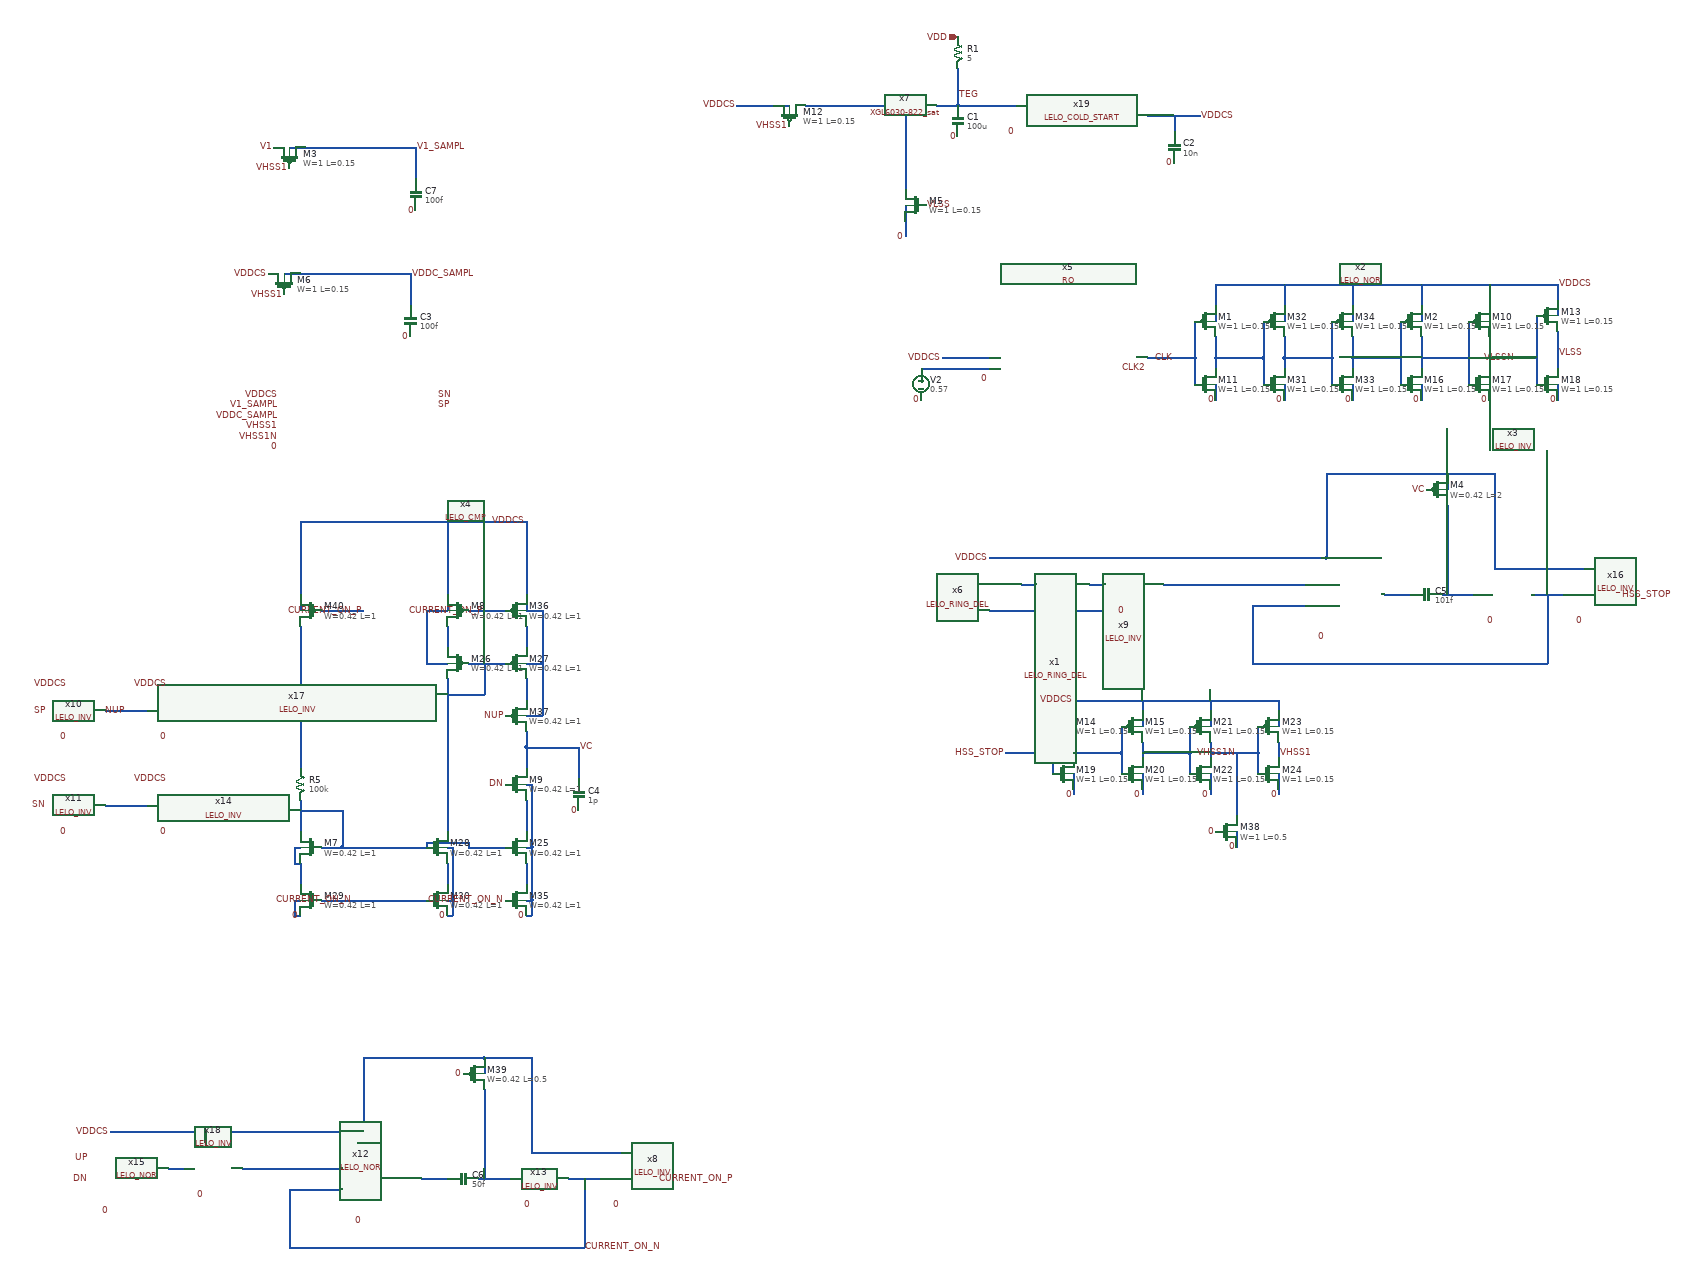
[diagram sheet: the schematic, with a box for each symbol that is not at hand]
v {xschem version=3.4.8RC file_version=1.2}
G {}
K {}
V {}
S {}
E {}
N -200 -370 -200 -300 {lab=TEG}
N -490 -300 -430 -300 {lab=V1}
N -430 -300 -300 -300 {lab=V1}
N -300 -300 -300 -140 {lab=V1}
N -300 -110 -300 -50 {lab=0}
N -240 -300 -220 -300 {lab=TEG}
N 290 230 290 260 {lab=0}
N 160 180 250 180 {lab=CLK}
N 680 140 680 200 {lab=#net1}
N 680 230 680 260 {lab=0}
N 640 110 640 230 {lab=#net2}
N 290 180 380 180 {lab=#net3}
N -220 -300 -200 -300 {lab=TEG}
N 60 610 80 610 {lab=#net4}
N 50 610 60 610 {lab=#net4}
N 810 140 810 200 {lab=VLSSN}
N 810 230 810 260 {lab=0}
N 770 110 770 230 {lab=#net1}
N 680 180 770 180 {lab=#net1}
N 940 130 940 200 {lab=VLSS}
N 940 230 940 260 {lab=0}
N 900 100 900 230 {lab=VLSSN}
N 810 180 900 180 {lab=VLSSN}
N -550 -300 -520 -300 {lab=VDDCS}
N -1330 -220 -1230 -220 {lab=V1_SAMPL}
N -1230 -220 -1230 -160 {lab=V1_SAMPL}
N -1470 -220 -1440 -220 {lab=V1_SAMPL}
N -1440 -220 -1330 -220 {lab=V1_SAMPL}
N -1340 20 -1240 20 {lab=VDDC_SAMPL}
N -1240 20 -1240 80 {lab=VDDC_SAMPL}
N -1480 20 -1450 20 {lab=VDDC_SAMPL}
N -1450 20 -1340 20 {lab=VDDC_SAMPL}
N -1020 920 -920 920 {lab=VC}
N -920 920 -920 980 {lab=VC}
N -1020 920 -1020 960 {lab=VC}
N -1020 1020 -1020 1080 {lab=#net5}
N -270 200 -140 200 {lab=#net6}
N -1020 790 -1020 830 {lab=#net7}
N -1020 890 -1020 920 {lab=VC}
N 290 40 870 40 {lab=#net8}
N 680 40 680 80 {lab=#net8}
N 810 40 810 80 {lab=#net8}
N 940 40 940 70 {lab=#net8}
N 290 40 290 80 {lab=#net8}
N 290 140 290 180 {lab=#net3}
N 290 180 290 200 {lab=#net3}
N 250 110 250 180 {lab=CLK}
N 250 180 250 230 {lab=CLK}
N 20 830 20 850 {lab=VDDCS}
N 150 830 150 850 {lab=VDDCS}
N 20 970 20 1000 {lab=0}
N 150 970 150 1000 {lab=0}
N -110 930 -20 930 {lab=HSS_STOP}
N -20 880 -20 930 {lab=HSS_STOP}
N -20 930 -20 970 {lab=HSS_STOP}
N 20 910 20 940 {lab=#net9}
N 20 1000 20 1010 {lab=0}
N 20 930 110 930 {lab=#net9}
N 110 880 110 930 {lab=#net9}
N 110 930 110 970 {lab=#net9}
N 150 910 150 940 {lab=#net10}
N 150 1000 150 1010 {lab=0}
N 280 830 280 850 {lab=VDDCS}
N 280 970 280 1000 {lab=0}
N 150 930 240 930 {lab=#net10}
N 240 880 240 930 {lab=#net10}
N 240 930 240 970 {lab=#net10}
N 280 910 280 940 {lab=VHSS1N}
N 280 1000 280 1010 {lab=0}
N 410 830 410 850 {lab=VDDCS}
N 410 970 410 1000 {lab=0}
N 370 880 370 930 {lab=VHSS1N}
N 370 930 370 970 {lab=VHSS1N}
N 410 910 410 940 {lab=VHSS1}
N 410 1000 410 1010 {lab=0}
N 290 80 290 110 {lab=#net8}
N 680 80 680 110 {lab=#net8}
N 810 80 810 110 {lab=#net8}
N 940 70 940 100 {lab=#net8}
N 20 850 20 880 {lab=VDDCS}
N 150 850 150 880 {lab=VDDCS}
N 280 850 280 880 {lab=VDDCS}
N 410 850 410 880 {lab=VDDCS}
N -230 180 -140 180 {lab=#net11}
N 190 610 270 610 {lab=#net12}
N 420 230 420 260 {lab=0}
N 420 180 510 180 {lab=#net13}
N 420 40 420 80 {lab=#net8}
N 420 140 420 180 {lab=#net13}
N 420 180 420 200 {lab=#net13}
N 380 110 380 180 {lab=#net3}
N 380 180 380 230 {lab=#net3}
N 420 80 420 110 {lab=#net8}
N 550 230 550 260 {lab=0}
N 550 180 640 180 {lab=#net2}
N 550 40 550 80 {lab=#net8}
N 550 140 550 180 {lab=#net2}
N 550 180 550 200 {lab=#net2}
N 510 110 510 180 {lab=#net13}
N 510 180 510 230 {lab=#net13}
N 550 80 550 110 {lab=#net8}
N 270 610 460 610 {lab=#net12}
N 890 630 950 630 {lab=#net14}
N 820 580 990 580 {lab=VDDCS}
N 720 630 780 630 {lab=#net15}
N 610 630 660 630 {lab=#net16}
N 490 560 500 560 {lab=VDDCS}
N 360 760 920 760 {lab=#net14}
N 360 650 460 650 {lab=#net14}
N 730 460 730 630 {lab=#net15}
N 730 400 730 430 {lab=VDDCS}
N 360 650 360 760 {lab=#net14}
N 920 630 920 760 {lab=#net14}
N 820 400 820 580 {lab=VDDCS}
N 730 400 820 400 {lab=VDDCS}
N 500 400 730 400 {lab=VDDCS}
N 500 400 500 560 {lab=VDDCS}
N 120 560 500 560 {lab=VDDCS}
N -140 560 120 560 {lab=VDDCS}
N -140 660 120 660 {lab=0}
N -80 610 -50 610 {lab=#net17}
N -1450 1020 -1450 1080 {lab=#net18}
N -1370 1040 -1370 1110 {lab=#net18}
N -1450 1040 -1370 1040 {lab=#net18}
N -1130 760 -1060 760 {lab=#net19}
N -1170 820 -1100 820 {lab=#net19}
N -1100 760 -1100 820 {lab=#net19}
N -1450 1140 -1450 1180 {lab=#net20}
N -1020 1140 -1020 1180 {lab=#net21}
N -1410 1110 -1370 1110 {lab=#net18}
N -1370 1110 -1210 1110 {lab=#net18}
N -1170 790 -1170 1080 {lab=#net19}
N -1170 1140 -1170 1180 {lab=#net22}
N -1450 690 -1450 960 {lab=#net23}
N -1130 660 -1060 660 {lab=CURRENT_ON_P}
N -1020 690 -1020 730 {lab=#net24}
N -1170 690 -1170 730 {lab=#net25}
N -1130 1110 -1060 1110 {lab=#net18}
N -1170 1110 -1160 1110 {lab=0}
N -1160 1110 -1160 1210 {lab=0}
N -1170 1210 -1160 1210 {lab=0}
N -1170 1210 -1160 1210 {lab=0}
N -1160 1210 -1160 1240 {lab=0}
N -1170 1240 -1160 1240 {lab=0}
N -1020 1110 -1010 1110 {lab=0}
N -1010 1110 -1010 1210 {lab=0}
N -1020 1210 -1010 1210 {lab=0}
N -1020 1210 -1010 1210 {lab=0}
N -1010 1210 -1010 1240 {lab=0}
N -1020 1240 -1010 1240 {lab=0}
N -1460 1210 -1450 1210 {lab=0}
N -1460 1210 -1460 1240 {lab=0}
N -1460 1240 -1450 1240 {lab=0}
N -1460 1110 -1450 1110 {lab=#net20}
N -1460 1110 -1460 1140 {lab=#net20}
N -1460 1140 -1450 1140 {lab=#net20}
N -1560 1720 -1370 1720 {lab=#net26}
N -940 1740 -880 1740 {lab=CURRENT_ON_N}
N -1010 1690 -840 1690 {lab=VDDCS}
N -1110 1740 -1050 1740 {lab=#net27}
N -1220 1740 -1170 1740 {lab=#net28}
N -1340 1670 -1330 1670 {lab=VDDCS}
N -1470 1870 -910 1870 {lab=CURRENT_ON_N}
N -1470 1760 -1370 1760 {lab=CURRENT_ON_N}
N -1100 1570 -1100 1740 {lab=#net27}
N -1100 1510 -1100 1540 {lab=VDDCS}
N -1470 1760 -1470 1870 {lab=CURRENT_ON_N}
N -910 1740 -910 1870 {lab=CURRENT_ON_N}
N -1010 1510 -1010 1690 {lab=VDDCS}
N -1100 1510 -1010 1510 {lab=VDDCS}
N -1330 1510 -1100 1510 {lab=VDDCS}
N -1330 1510 -1330 1670 {lab=VDDCS}
N -1410 1210 -1350 1210 {lab=CURRENT_ON_N}
N -1350 1210 -1210 1210 {lab=CURRENT_ON_N}
N -1410 660 -1330 660 {lab=CURRENT_ON_P}
N -1020 490 -1020 630 {lab=VDDCS}
N -1450 490 -1020 490 {lab=VDDCS}
N -1450 490 -1450 630 {lab=VDDCS}
N -1170 490 -1170 630 {lab=VDDCS}
N -1210 1100 -1210 1110 {lab=#net18}
N -1210 1100 -1130 1100 {lab=#net18}
N -1130 1100 -1130 1110 {lab=#net18}
N -1210 760 -1170 760 {lab=VDDCS}
N -1210 660 -1210 760 {lab=VDDCS}
N -1210 660 -1170 660 {lab=VDDCS}
N -1170 630 -1170 660 {lab=VDDCS}
N -1020 760 -990 760 {lab=VDDCS}
N -990 660 -990 760 {lab=VDDCS}
N -1020 660 -990 660 {lab=VDDCS}
N -1020 630 -1020 660 {lab=VDDCS}
N -1450 630 -1450 660 {lab=VDDCS}
N -1020 860 -990 860 {lab=VDDCS}
N -990 760 -990 860 {lab=VDDCS}
N -1820 1030 -1740 1030 {lab=#net29}
N -1820 850 -1740 850 {lab=NUP}
N -1700 1720 -1670 1720 {lab=#net30}
N -1810 1650 -1330 1650 {lab=VDDCS}
N -1630 1650 -1630 1670 {lab=VDDCS}
N -1020 990 -1010 990 {lab=0}
N -1010 990 -1010 1110 {lab=0}
N 20 830 410 830 {lab=VDDCS}
N 280 930 370 930 {lab=VHSS1N}
N 211 -280 211 -250 {lab=VDDCS}
N 161 -280 211 -280 {lab=VDDCS}
N -130 -300 -89 -300 {lab=TEG}
N -200 -300 -130 -300 {lab=TEG}
N 210 -280 260 -280 {lab=VDDCS}
N -620 -300 -550 -300 {lab=VDDCS}
N 870 40 940 40 {lab=#net8}
N 330 1080 330 1110 {lab=0}
N 330 930 330 1050 {lab=VHSS1N}
C {devices/ipin.sym} -200 -430 0 0 {name=p2 lab=VDD}
C {devices/lab_pin.sym} -300 -300 1 0 {name=p3 sig_type=std_logic lab=V1}
C {devices/res.sym} -200 -400 0 0 {name=R1
value=5
footprint=1206
device=resistor
m=1}
C {devices/lab_pin.sym} -300 -50 1 1 {name=p29 sig_type=std_logic lab=0}
C {devices/capa.sym} -1230 -130 0 0 {name=C7
m=1
value=100f
footprint=1206
device="ceramic capacitor"}
C {devices/lab_pin.sym} -1230 -100 1 1 {name=p34 sig_type=std_logic lab=0}
C {devices/lab_pin.sym} 20 1010 3 0 {name=p77 sig_type=std_logic lab=0}
C {LELO_SVOD_SKY130A/RO.sym} 10 200 0 0 {name=x5}
C {devices/lab_pin.sym} -140 220 3 0 {name=p13 sig_type=std_logic lab=0}
C {devices/lab_pin.sym} 210 180 1 1 {name=p14 sig_type=std_logic lab=CLK}
C {devices/lab_pin.sym} 290 260 3 0 {name=p15 sig_type=std_logic lab=0}
C {devices/lab_pin.sym} 680 260 3 0 {name=p17 sig_type=std_logic lab=0}
C {devices/lab_pin.sym} 940 170 0 1 {name=p30 sig_type=std_logic lab=VLSS}
C {devices/lab_pin.sym} -260 -110 0 1 {name=p66 sig_type=std_logic lab=VLSS}
C {devices/lab_pin.sym} -180 610 0 0 {name=p23 sig_type=std_logic lab=VLSS}
C {sky130_fd_pr/pfet_01v8.sym} -520 -280 3 0 {name=M12
W=1
L=0.15
nf=1
mult=800
ad="expr('int((@nf + 1)/2) * @W / @nf * 0.29')"
pd="expr('2*int((@nf + 1)/2) * (@W / @nf + 0.29)')"
as="expr('int((@nf + 2)/2) * @W / @nf * 0.29')"
ps="expr('2*int((@nf + 2)/2) * (@W / @nf + 0.29)')"
nrd="expr('0.29 / @W ')" nrs="expr('0.29 / @W ')"
sa=0 sb=0 sd=0
model=pfet_01v8
spiceprefix=X
}
C {devices/lab_pin.sym} 150 1010 3 0 {name=p4 sig_type=std_logic lab=0}
C {LELO_SVOD_SKY130A/LELO_INV.sym} 1010 630 0 0 {name=x16}
C {devices/capa.sym} -200 -270 0 0 {name=C1
m=1
value=100u
footprint=1206
device="ceramic capacitor"}
C {devices/lab_pin.sym} -200 -240 1 1 {name=p7 sig_type=std_logic lab=0}
C {LELO_SVOD_SKY130A/LELO_INV.sym} 140 610 0 0 {name=x9}
C {sky130_fd_pr/nfet_01v8_lvt.sym} -280 -110 0 1 {name=M5
W=1
L=0.15
nf=1
mult=6500
ad="expr('int((@nf + 1)/2) * @W / @nf * 0.29')"
pd="expr('2*int((@nf + 1)/2) * (@W / @nf + 0.29)')"
as="expr('int((@nf + 2)/2) * @W / @nf * 0.29')"
ps="expr('2*int((@nf + 2)/2) * (@W / @nf + 0.29)')"
nrd="expr('0.29 / @W ')" nrs="expr('0.29 / @W ')"
sa=0 sb=0 sd=0
model=nfet_01v8_lvt
spiceprefix=X
}
C {devices/lab_pin.sym} 810 260 3 0 {name=p51 sig_type=std_logic lab=0}
C {devices/lab_pin.sym} 940 260 3 0 {name=p90 sig_type=std_logic lab=0}
C {devices/lab_pin.sym} -200 -320 2 0 {name=p93 sig_type=std_logic lab=TEG}
C {devices/lab_pin.sym} 160 200 1 1 {name=p94 sig_type=std_logic lab=CLK2}
C {devices/lab_pin.sym} -620 -300 2 1 {name=p24 sig_type=std_logic lab=VDDCS}
C {LELO_SVOD_SKY130A/LELO_CMP.sym} -1340 300 0 0 {name=x4}
C {devices/lab_pin.sym} -1470 -180 1 1 {name=p10 sig_type=std_logic lab=VHSS1}
C {sky130_fd_pr/pfet_01v8.sym} -1470 -200 1 1 {name=M3
W=1
L=0.15
nf=1
mult=1
ad="expr('int((@nf + 1)/2) * @W / @nf * 0.29')"
pd="expr('2*int((@nf + 1)/2) * (@W / @nf + 0.29)')"
as="expr('int((@nf + 2)/2) * @W / @nf * 0.29')"
ps="expr('2*int((@nf + 2)/2) * (@W / @nf + 0.29)')"
nrd="expr('0.29 / @W ')" nrs="expr('0.29 / @W ')"
sa=0 sb=0 sd=0
model=pfet_01v8
spiceprefix=X
}
C {devices/lab_pin.sym} -1500 -220 0 0 {name=p12 sig_type=std_logic lab=V1}
C {devices/capa.sym} -1240 110 0 0 {name=C3
m=1
value=100f
footprint=1206
device="ceramic capacitor"}
C {devices/lab_pin.sym} -1240 140 1 1 {name=p26 sig_type=std_logic lab=0}
C {devices/lab_pin.sym} -1480 60 1 1 {name=p27 sig_type=std_logic lab=VHSS1}
C {sky130_fd_pr/pfet_01v8.sym} -1480 40 1 1 {name=M6
W=1
L=0.15
nf=1
mult=1
ad="expr('int((@nf + 1)/2) * @W / @nf * 0.29')"
pd="expr('2*int((@nf + 1)/2) * (@W / @nf + 0.29)')"
as="expr('int((@nf + 2)/2) * @W / @nf * 0.29')"
ps="expr('2*int((@nf + 2)/2) * (@W / @nf + 0.29)')"
nrd="expr('0.29 / @W ')" nrs="expr('0.29 / @W ')"
sa=0 sb=0 sd=0
model=pfet_01v8
spiceprefix=X
}
C {devices/lab_pin.sym} -1240 20 0 1 {name=p36 sig_type=std_logic lab=VDDC_SAMPL}
C {devices/lab_pin.sym} -1230 -220 0 1 {name=p37 sig_type=std_logic lab=V1_SAMPL}
C {devices/lab_pin.sym} -1490 270 0 0 {name=p38 sig_type=std_logic lab=V1_SAMPL}
C {devices/lab_pin.sym} -1490 290 0 0 {name=p39 sig_type=std_logic lab=VDDC_SAMPL}
C {devices/lab_pin.sym} -1490 350 1 1 {name=p40 sig_type=std_logic lab=0}
C {devices/capa.sym} -920 1010 0 0 {name=C4
m=1
value=1p
footprint=1206
device="ceramic capacitor"}
C {devices/lab_pin.sym} -920 1040 1 1 {name=p46 sig_type=std_logic lab=0}
C {devices/lab_pin.sym} -920 920 0 1 {name=p47 sig_type=std_logic lab=VC}
C {sky130_fd_pr/nfet_01v8.sym} -1040 990 0 0 {name=M9
W=0.42
L=1
nf=1 
mult=1
ad="expr('int((@nf + 1)/2) * @W / @nf * 0.29')"
pd="expr('2*int((@nf + 1)/2) * (@W / @nf + 0.29)')"
as="expr('int((@nf + 2)/2) * @W / @nf * 0.29')"
ps="expr('2*int((@nf + 2)/2) * (@W / @nf + 0.29)')"
nrd="expr('0.29 / @W ')" nrs="expr('0.29 / @W ')"
sa=0 sb=0 sd=0
model=nfet_01v8
spiceprefix=X
}
C {devices/lab_pin.sym} -1190 270 0 1 {name=p53 sig_type=std_logic lab=SP}
C {devices/lab_pin.sym} -1190 250 0 1 {name=p69 sig_type=std_logic lab=SN}
C {devices/vsource.sym} -270 230 0 0 {name=V2 value=0.57 savecurrent=false}
C {devices/lab_pin.sym} -270 260 1 1 {name=p71 sig_type=std_logic lab=0}
C {devices/lab_pin.sym} 860 180 3 1 {name=p70 sig_type=std_logic lab=VLSSN}
C {sky130_fd_pr/nfet_01v8.sym} 270 230 0 0 {name=M11
W=1
L=0.15
nf=1 
mult=1
ad="expr('int((@nf + 1)/2) * @W / @nf * 0.29')"
pd="expr('2*int((@nf + 1)/2) * (@W / @nf + 0.29)')"
as="expr('int((@nf + 2)/2) * @W / @nf * 0.29')"
ps="expr('2*int((@nf + 2)/2) * (@W / @nf + 0.29)')"
nrd="expr('0.29 / @W ')" nrs="expr('0.29 / @W ')"
sa=0 sb=0 sd=0
model=nfet_01v8
spiceprefix=X
}
C {sky130_fd_pr/nfet_01v8.sym} 660 230 0 0 {name=M16
W=1
L=0.15
nf=1 
mult=4
ad="expr('int((@nf + 1)/2) * @W / @nf * 0.29')"
pd="expr('2*int((@nf + 1)/2) * (@W / @nf + 0.29)')"
as="expr('int((@nf + 2)/2) * @W / @nf * 0.29')"
ps="expr('2*int((@nf + 2)/2) * (@W / @nf + 0.29)')"
nrd="expr('0.29 / @W ')" nrs="expr('0.29 / @W ')"
sa=0 sb=0 sd=0
model=nfet_01v8
spiceprefix=X
}
C {sky130_fd_pr/nfet_01v8.sym} 790 230 0 0 {name=M17
W=1
L=0.15
nf=1 
mult=9
ad="expr('int((@nf + 1)/2) * @W / @nf * 0.29')"
pd="expr('2*int((@nf + 1)/2) * (@W / @nf + 0.29)')"
as="expr('int((@nf + 2)/2) * @W / @nf * 0.29')"
ps="expr('2*int((@nf + 2)/2) * (@W / @nf + 0.29)')"
nrd="expr('0.29 / @W ')" nrs="expr('0.29 / @W ')"
sa=0 sb=0 sd=0
model=nfet_01v8
spiceprefix=X
}
C {sky130_fd_pr/nfet_01v8.sym} 920 230 0 0 {name=M18
W=1
L=0.15
nf=1 
mult=27
ad="expr('int((@nf + 1)/2) * @W / @nf * 0.29')"
pd="expr('2*int((@nf + 1)/2) * (@W / @nf + 0.29)')"
as="expr('int((@nf + 2)/2) * @W / @nf * 0.29')"
ps="expr('2*int((@nf + 2)/2) * (@W / @nf + 0.29)')"
nrd="expr('0.29 / @W ')" nrs="expr('0.29 / @W ')"
sa=0 sb=0 sd=0
model=nfet_01v8
spiceprefix=X
}
C {sky130_fd_pr/nfet_01v8.sym} 0 970 0 0 {name=M19
W=1
L=0.15
nf=1 
mult=1
ad="expr('int((@nf + 1)/2) * @W / @nf * 0.29')"
pd="expr('2*int((@nf + 1)/2) * (@W / @nf + 0.29)')"
as="expr('int((@nf + 2)/2) * @W / @nf * 0.29')"
ps="expr('2*int((@nf + 2)/2) * (@W / @nf + 0.29)')"
nrd="expr('0.29 / @W ')" nrs="expr('0.29 / @W ')"
sa=0 sb=0 sd=0
model=nfet_01v8
spiceprefix=X
}
C {sky130_fd_pr/nfet_01v8.sym} 130 970 0 0 {name=M20
W=1
L=0.15
nf=1 
mult=3
ad="expr('int((@nf + 1)/2) * @W / @nf * 0.29')"
pd="expr('2*int((@nf + 1)/2) * (@W / @nf + 0.29)')"
as="expr('int((@nf + 2)/2) * @W / @nf * 0.29')"
ps="expr('2*int((@nf + 2)/2) * (@W / @nf + 0.29)')"
nrd="expr('0.29 / @W ')" nrs="expr('0.29 / @W ')"
sa=0 sb=0 sd=0
model=nfet_01v8
spiceprefix=X
}
C {devices/lab_pin.sym} 410 930 0 1 {name=p18 sig_type=std_logic lab=VHSS1}
C {devices/lab_pin.sym} 280 1010 3 0 {name=p21 sig_type=std_logic lab=0}
C {sky130_fd_pr/nfet_01v8.sym} 260 970 0 0 {name=M22
W=1
L=0.15
nf=1 
mult=9
ad="expr('int((@nf + 1)/2) * @W / @nf * 0.29')"
pd="expr('2*int((@nf + 1)/2) * (@W / @nf + 0.29)')"
as="expr('int((@nf + 2)/2) * @W / @nf * 0.29')"
ps="expr('2*int((@nf + 2)/2) * (@W / @nf + 0.29)')"
nrd="expr('0.29 / @W ')" nrs="expr('0.29 / @W ')"
sa=0 sb=0 sd=0
model=nfet_01v8
spiceprefix=X
}
C {devices/lab_pin.sym} 410 1010 3 0 {name=p55 sig_type=std_logic lab=0}
C {sky130_fd_pr/nfet_01v8.sym} 390 970 0 0 {name=M24
W=1
L=0.15
nf=1 
mult=27
ad="expr('int((@nf + 1)/2) * @W / @nf * 0.29')"
pd="expr('2*int((@nf + 1)/2) * (@W / @nf + 0.29)')"
as="expr('int((@nf + 2)/2) * @W / @nf * 0.29')"
ps="expr('2*int((@nf + 2)/2) * (@W / @nf + 0.29)')"
nrd="expr('0.29 / @W ')" nrs="expr('0.29 / @W ')"
sa=0 sb=0 sd=0
model=nfet_01v8
spiceprefix=X
}
C {sky130_fd_pr/pfet_01v8_hvt.sym} 270 110 0 0 {name=M1
W=1
L=0.15
nf=1
mult=1
ad="expr('int((@nf + 1)/2) * @W / @nf * 0.29')"
pd="expr('2*int((@nf + 1)/2) * (@W / @nf + 0.29)')"
as="expr('int((@nf + 2)/2) * @W / @nf * 0.29')"
ps="expr('2*int((@nf + 2)/2) * (@W / @nf + 0.29)')"
nrd="expr('0.29 / @W ')" nrs="expr('0.29 / @W ')"
sa=0 sb=0 sd=0
model=pfet_01v8_hvt
spiceprefix=X
}
C {sky130_fd_pr/pfet_01v8_hvt.sym} 660 110 0 0 {name=M2
W=1
L=0.15
nf=1
mult=4
ad="expr('int((@nf + 1)/2) * @W / @nf * 0.29')"
pd="expr('2*int((@nf + 1)/2) * (@W / @nf + 0.29)')"
as="expr('int((@nf + 2)/2) * @W / @nf * 0.29')"
ps="expr('2*int((@nf + 2)/2) * (@W / @nf + 0.29)')"
nrd="expr('0.29 / @W ')" nrs="expr('0.29 / @W ')"
sa=0 sb=0 sd=0
model=pfet_01v8_hvt
spiceprefix=X
}
C {sky130_fd_pr/pfet_01v8_hvt.sym} 790 110 0 0 {name=M10
W=1
L=0.15
nf=1
mult=9
ad="expr('int((@nf + 1)/2) * @W / @nf * 0.29')"
pd="expr('2*int((@nf + 1)/2) * (@W / @nf + 0.29)')"
as="expr('int((@nf + 2)/2) * @W / @nf * 0.29')"
ps="expr('2*int((@nf + 2)/2) * (@W / @nf + 0.29)')"
nrd="expr('0.29 / @W ')" nrs="expr('0.29 / @W ')"
sa=0 sb=0 sd=0
model=pfet_01v8_hvt
spiceprefix=X
}
C {sky130_fd_pr/pfet_01v8_hvt.sym} 920 100 0 0 {name=M13
W=1
L=0.15
nf=1
mult=27
ad="expr('int((@nf + 1)/2) * @W / @nf * 0.29')"
pd="expr('2*int((@nf + 1)/2) * (@W / @nf + 0.29)')"
as="expr('int((@nf + 2)/2) * @W / @nf * 0.29')"
ps="expr('2*int((@nf + 2)/2) * (@W / @nf + 0.29)')"
nrd="expr('0.29 / @W ')" nrs="expr('0.29 / @W ')"
sa=0 sb=0 sd=0
model=pfet_01v8_hvt
spiceprefix=X
}
C {sky130_fd_pr/pfet_01v8_hvt.sym} 0 880 0 0 {name=M14
W=1
L=0.15
nf=1
mult=1
ad="expr('int((@nf + 1)/2) * @W / @nf * 0.29')"
pd="expr('2*int((@nf + 1)/2) * (@W / @nf + 0.29)')"
as="expr('int((@nf + 2)/2) * @W / @nf * 0.29')"
ps="expr('2*int((@nf + 2)/2) * (@W / @nf + 0.29)')"
nrd="expr('0.29 / @W ')" nrs="expr('0.29 / @W ')"
sa=0 sb=0 sd=0
model=pfet_01v8_hvt
spiceprefix=X
}
C {sky130_fd_pr/pfet_01v8_hvt.sym} 130 880 0 0 {name=M15
W=1
L=0.15
nf=1
mult=3
ad="expr('int((@nf + 1)/2) * @W / @nf * 0.29')"
pd="expr('2*int((@nf + 1)/2) * (@W / @nf + 0.29)')"
as="expr('int((@nf + 2)/2) * @W / @nf * 0.29')"
ps="expr('2*int((@nf + 2)/2) * (@W / @nf + 0.29)')"
nrd="expr('0.29 / @W ')" nrs="expr('0.29 / @W ')"
sa=0 sb=0 sd=0
model=pfet_01v8_hvt
spiceprefix=X
}
C {sky130_fd_pr/pfet_01v8_hvt.sym} 260 880 0 0 {name=M21
W=1
L=0.15
nf=1
mult=9
ad="expr('int((@nf + 1)/2) * @W / @nf * 0.29')"
pd="expr('2*int((@nf + 1)/2) * (@W / @nf + 0.29)')"
as="expr('int((@nf + 2)/2) * @W / @nf * 0.29')"
ps="expr('2*int((@nf + 2)/2) * (@W / @nf + 0.29)')"
nrd="expr('0.29 / @W ')" nrs="expr('0.29 / @W ')"
sa=0 sb=0 sd=0
model=pfet_01v8_hvt
spiceprefix=X
}
C {sky130_fd_pr/pfet_01v8_hvt.sym} 390 880 0 0 {name=M23
W=1
L=0.15
nf=1
mult=27
ad="expr('int((@nf + 1)/2) * @W / @nf * 0.29')"
pd="expr('2*int((@nf + 1)/2) * (@W / @nf + 0.29)')"
as="expr('int((@nf + 2)/2) * @W / @nf * 0.29')"
ps="expr('2*int((@nf + 2)/2) * (@W / @nf + 0.29)')"
nrd="expr('0.29 / @W ')" nrs="expr('0.29 / @W ')"
sa=0 sb=0 sd=0
model=pfet_01v8_hvt
spiceprefix=X
}
C {devices/lab_pin.sym} 330 930 3 1 {name=p97 sig_type=std_logic lab=VHSS1N}
C {devices/lab_pin.sym} 420 260 3 0 {name=p88 sig_type=std_logic lab=0}
C {sky130_fd_pr/nfet_01v8.sym} 400 230 0 0 {name=M31
W=1
L=0.15
nf=1 
mult=1
ad="expr('int((@nf + 1)/2) * @W / @nf * 0.29')"
pd="expr('2*int((@nf + 1)/2) * (@W / @nf + 0.29)')"
as="expr('int((@nf + 2)/2) * @W / @nf * 0.29')"
ps="expr('2*int((@nf + 2)/2) * (@W / @nf + 0.29)')"
nrd="expr('0.29 / @W ')" nrs="expr('0.29 / @W ')"
sa=0 sb=0 sd=0
model=nfet_01v8
spiceprefix=X
}
C {sky130_fd_pr/pfet_01v8_hvt.sym} 400 110 0 0 {name=M32
W=1
L=0.15
nf=1
mult=1
ad="expr('int((@nf + 1)/2) * @W / @nf * 0.29')"
pd="expr('2*int((@nf + 1)/2) * (@W / @nf + 0.29)')"
as="expr('int((@nf + 2)/2) * @W / @nf * 0.29')"
ps="expr('2*int((@nf + 2)/2) * (@W / @nf + 0.29)')"
nrd="expr('0.29 / @W ')" nrs="expr('0.29 / @W ')"
sa=0 sb=0 sd=0
model=pfet_01v8_hvt
spiceprefix=X
}
C {devices/lab_pin.sym} 550 260 3 0 {name=p89 sig_type=std_logic lab=0}
C {sky130_fd_pr/nfet_01v8.sym} 530 230 0 0 {name=M33
W=1
L=0.15
nf=1 
mult=2
ad="expr('int((@nf + 1)/2) * @W / @nf * 0.29')"
pd="expr('2*int((@nf + 1)/2) * (@W / @nf + 0.29)')"
as="expr('int((@nf + 2)/2) * @W / @nf * 0.29')"
ps="expr('2*int((@nf + 2)/2) * (@W / @nf + 0.29)')"
nrd="expr('0.29 / @W ')" nrs="expr('0.29 / @W ')"
sa=0 sb=0 sd=0
model=nfet_01v8
spiceprefix=X
}
C {sky130_fd_pr/pfet_01v8_hvt.sym} 530 110 0 0 {name=M34
W=1
L=0.15
nf=1
mult=2
ad="expr('int((@nf + 1)/2) * @W / @nf * 0.29')"
pd="expr('2*int((@nf + 1)/2) * (@W / @nf + 0.29)')"
as="expr('int((@nf + 2)/2) * @W / @nf * 0.29')"
ps="expr('2*int((@nf + 2)/2) * (@W / @nf + 0.29)')"
nrd="expr('0.29 / @W ')" nrs="expr('0.29 / @W ')"
sa=0 sb=0 sd=0
model=pfet_01v8_hvt
spiceprefix=X
}
C {LELO_SVOD_SKY130A/XGL6030-822_sat.sym} -270 -300 1 0 {name=x7}
C {LELO_SVOD_SKY130A/LELO_INV.sym} -1870 850 0 0 {name=x10}
C {devices/lab_pin.sym} -1890 800 0 0 {name=p52 sig_type=std_logic lab=VDDCS}
C {devices/lab_pin.sym} -1890 900 0 0 {name=p56 sig_type=std_logic lab=0}
C {devices/lab_pin.sym} 1060 630 0 1 {name=p57 sig_type=std_logic lab=HSS_STOP}
C {LELO_SVOD_SKY130A/LELO_NOR.sym} 520 630 0 0 {name=x2}
C {devices/capa.sym} 690 630 1 0 {name=C5
m=1
value=101f
footprint=1206
device="ceramic capacitor"}
C {devices/lab_pin.sym} 120 660 3 0 {name=p6 sig_type=std_logic lab=0}
C {devices/lab_pin.sym} 500 710 3 0 {name=p20 sig_type=std_logic lab=0}
C {LELO_SVOD_SKY130A/LELO_INV.sym} 840 630 0 0 {name=x3}
C {devices/lab_pin.sym} 820 680 3 0 {name=p22 sig_type=std_logic lab=0}
C {devices/lab_pin.sym} 990 680 3 0 {name=p25 sig_type=std_logic lab=0}
C {devices/lab_pin.sym} 690 430 0 0 {name=p31 sig_type=std_logic lab=VC}
C {devices/lab_pin.sym} -1490 310 0 0 {name=p19 sig_type=std_logic lab=VHSS1}
C {devices/lab_pin.sym} -1490 330 2 1 {name=p33 sig_type=std_logic lab=VHSS1N}
C {LELO_SVOD_SKY130A/LELO_RING_DEL.sym} 10 610 0 0 {name=x1}
C {LELO_SVOD_SKY130A/LELO_RING_DEL.sym} -120 610 0 0 {name=x6}
C {devices/res.sym} -1450 990 0 0 {name=R5
value=100k
footprint=1206
device=resistor
m=1}
C {sky130_fd_pr/nfet_01v8.sym} -1430 1110 0 1 {name=M7
W=0.42
L=1
nf=1 
mult=10
ad="expr('int((@nf + 1)/2) * @W / @nf * 0.29')"
pd="expr('2*int((@nf + 1)/2) * (@W / @nf + 0.29)')"
as="expr('int((@nf + 2)/2) * @W / @nf * 0.29')"
ps="expr('2*int((@nf + 2)/2) * (@W / @nf + 0.29)')"
nrd="expr('0.29 / @W ')" nrs="expr('0.29 / @W ')"
sa=0 sb=0 sd=0
model=nfet_01v8
spiceprefix=X
}
C {sky130_fd_pr/nfet_01v8.sym} -1040 1110 0 0 {name=M25
W=0.42
L=1
nf=1 
mult=1
ad="expr('int((@nf + 1)/2) * @W / @nf * 0.29')"
pd="expr('2*int((@nf + 1)/2) * (@W / @nf + 0.29)')"
as="expr('int((@nf + 2)/2) * @W / @nf * 0.29')"
ps="expr('2*int((@nf + 2)/2) * (@W / @nf + 0.29)')"
nrd="expr('0.29 / @W ')" nrs="expr('0.29 / @W ')"
sa=0 sb=0 sd=0
model=nfet_01v8
spiceprefix=X
}
C {sky130_fd_pr/nfet_01v8.sym} -1190 1110 0 0 {name=M28
W=0.42
L=1
nf=1 
mult=1
ad="expr('int((@nf + 1)/2) * @W / @nf * 0.29')"
pd="expr('2*int((@nf + 1)/2) * (@W / @nf + 0.29)')"
as="expr('int((@nf + 2)/2) * @W / @nf * 0.29')"
ps="expr('2*int((@nf + 2)/2) * (@W / @nf + 0.29)')"
nrd="expr('0.29 / @W ')" nrs="expr('0.29 / @W ')"
sa=0 sb=0 sd=0
model=nfet_01v8
spiceprefix=X
}
C {sky130_fd_pr/nfet_01v8.sym} -1430 1210 0 1 {name=M29
W=0.42
L=1
nf=1 
mult=1
ad="expr('int((@nf + 1)/2) * @W / @nf * 0.29')"
pd="expr('2*int((@nf + 1)/2) * (@W / @nf + 0.29)')"
as="expr('int((@nf + 2)/2) * @W / @nf * 0.29')"
ps="expr('2*int((@nf + 2)/2) * (@W / @nf + 0.29)')"
nrd="expr('0.29 / @W ')" nrs="expr('0.29 / @W ')"
sa=0 sb=0 sd=0
model=nfet_01v8
spiceprefix=X
}
C {sky130_fd_pr/nfet_01v8.sym} -1190 1210 0 0 {name=M30
W=0.42
L=1
nf=1 
mult=1
ad="expr('int((@nf + 1)/2) * @W / @nf * 0.29')"
pd="expr('2*int((@nf + 1)/2) * (@W / @nf + 0.29)')"
as="expr('int((@nf + 2)/2) * @W / @nf * 0.29')"
ps="expr('2*int((@nf + 2)/2) * (@W / @nf + 0.29)')"
nrd="expr('0.29 / @W ')" nrs="expr('0.29 / @W ')"
sa=0 sb=0 sd=0
model=nfet_01v8
spiceprefix=X
}
C {sky130_fd_pr/nfet_01v8.sym} -1040 1210 0 0 {name=M35
W=0.42
L=1
nf=1 
mult=1
ad="expr('int((@nf + 1)/2) * @W / @nf * 0.29')"
pd="expr('2*int((@nf + 1)/2) * (@W / @nf + 0.29)')"
as="expr('int((@nf + 2)/2) * @W / @nf * 0.29')"
ps="expr('2*int((@nf + 2)/2) * (@W / @nf + 0.29)')"
nrd="expr('0.29 / @W ')" nrs="expr('0.29 / @W ')"
sa=0 sb=0 sd=0
model=nfet_01v8
spiceprefix=X
}
C {LELO_SVOD_SKY130A/LELO_INV.sym} -820 1740 0 0 {name=x8}
C {LELO_SVOD_SKY130A/LELO_NOR.sym} -1310 1740 0 0 {name=x12}
C {devices/capa.sym} -1140 1740 1 0 {name=C6
m=1
value=50f
footprint=1206
device="ceramic capacitor"}
C {devices/lab_pin.sym} -1330 1820 3 0 {name=p48 sig_type=std_logic lab=0}
C {LELO_SVOD_SKY130A/LELO_INV.sym} -990 1740 0 0 {name=x13}
C {devices/lab_pin.sym} -1010 1790 3 0 {name=p50 sig_type=std_logic lab=0}
C {devices/lab_pin.sym} -840 1790 3 0 {name=p58 sig_type=std_logic lab=0}
C {devices/lab_pin.sym} -1140 1540 0 0 {name=p59 sig_type=std_logic lab=0}
C {devices/lab_pin.sym} -770 1740 0 1 {name=p42 sig_type=std_logic lab=CURRENT_ON_P}
C {devices/lab_pin.sym} -910 1870 0 1 {name=p44 sig_type=std_logic lab=CURRENT_ON_N}
C {devices/lab_pin.sym} -1350 1210 1 1 {name=p61 sig_type=std_logic lab=CURRENT_ON_N}
C {devices/lab_pin.sym} -1060 1210 1 1 {name=p62 sig_type=std_logic lab=CURRENT_ON_N}
C {devices/lab_pin.sym} -1330 660 3 1 {name=p63 sig_type=std_logic lab=CURRENT_ON_P}
C {devices/lab_pin.sym} -1100 660 3 1 {name=p64 sig_type=std_logic lab=CURRENT_ON_P}
C {devices/lab_pin.sym} -1450 1240 1 1 {name=p65 sig_type=std_logic lab=0}
C {devices/lab_pin.sym} -1170 1240 1 1 {name=p67 sig_type=std_logic lab=0}
C {devices/lab_pin.sym} -1020 1240 1 1 {name=p68 sig_type=std_logic lab=0}
C {devices/lab_pin.sym} -1630 850 0 1 {name=p72 sig_type=std_logic lab=UP}
C {sky130_fd_pr/pfet_01v8.sym} -1120 1540 0 0 {name=M39
W=0.42
L=0.5
nf=1
mult=1
ad="expr('int((@nf + 1)/2) * @W / @nf * 0.29')"
pd="expr('2*int((@nf + 1)/2) * (@W / @nf + 0.29)')"
as="expr('int((@nf + 2)/2) * @W / @nf * 0.29')"
ps="expr('2*int((@nf + 2)/2) * (@W / @nf + 0.29)')"
nrd="expr('0.29 / @W ')" nrs="expr('0.29 / @W ')"
sa=0 sb=0 sd=0
model=pfet_01v8
spiceprefix=X
}
C {devices/lab_pin.sym} -1930 850 0 0 {name=p75 sig_type=std_logic lab=SP}
C {LELO_SVOD_SKY130A/LELO_INV.sym} -1870 1030 0 0 {name=x11}
C {devices/lab_pin.sym} -1890 980 0 0 {name=p76 sig_type=std_logic lab=VDDCS}
C {devices/lab_pin.sym} -1890 1080 0 0 {name=p78 sig_type=std_logic lab=0}
C {devices/lab_pin.sym} -1630 1030 0 1 {name=p79 sig_type=std_logic lab=DN}
C {LELO_SVOD_SKY130A/LELO_INV.sym} -1680 1030 0 0 {name=x14}
C {devices/lab_pin.sym} -1700 980 0 0 {name=p81 sig_type=std_logic lab=VDDCS}
C {devices/lab_pin.sym} -1700 1080 0 0 {name=p82 sig_type=std_logic lab=0}
C {devices/lab_pin.sym} -1060 990 0 0 {name=p74 sig_type=std_logic lab=DN}
C {LELO_SVOD_SKY130A/LELO_NOR.sym} -1790 1720 0 0 {name=x15}
C {devices/lab_pin.sym} -1810 1800 3 0 {name=p80 sig_type=std_logic lab=0}
C {devices/lab_pin.sym} -1850 1740 0 0 {name=p83 sig_type=std_logic lab=DN}
C {LELO_SVOD_SKY130A/LELO_INV.sym} -1680 850 0 0 {name=x17}
C {devices/lab_pin.sym} -1700 800 0 0 {name=p84 sig_type=std_logic lab=VDDCS}
C {devices/lab_pin.sym} -1700 900 0 0 {name=p85 sig_type=std_logic lab=0}
C {devices/lab_pin.sym} -1780 850 3 1 {name=p91 sig_type=std_logic lab=NUP}
C {devices/lab_pin.sym} -1060 860 2 1 {name=p73 sig_type=std_logic lab=NUP}
C {devices/lab_pin.sym} -1850 1700 0 0 {name=p45 sig_type=std_logic lab=UP}
C {LELO_SVOD_SKY130A/LELO_INV.sym} -1610 1720 0 0 {name=x18}
C {devices/lab_pin.sym} -1630 1770 3 0 {name=p92 sig_type=std_logic lab=0}
C {devices/lab_pin.sym} -1930 1030 0 0 {name=p54 sig_type=std_logic lab=SN}
C {sky130_fd_pr/pfet_01v8_lvt.sym} 710 430 0 0 {name=M4
W=0.42
L=2
nf=1
mult=1
ad="expr('int((@nf + 1)/2) * @W / @nf * 0.29')"
pd="expr('2*int((@nf + 1)/2) * (@W / @nf + 0.29)')"
as="expr('int((@nf + 2)/2) * @W / @nf * 0.29')"
ps="expr('2*int((@nf + 2)/2) * (@W / @nf + 0.29)')"
nrd="expr('0.29 / @W ')" nrs="expr('0.29 / @W ')"
sa=0 sb=0 sd=0
model=pfet_01v8_lvt
spiceprefix=X
}
C {devices/lab_pin.sym} -520 -260 1 1 {name=p101 sig_type=std_logic lab=VHSS1}
C {devices/lab_pin.sym} -1020 490 3 1 {name=p1 sig_type=std_logic lab=VDDCS}
C {devices/lab_pin.sym} -1490 250 2 1 {name=p5 sig_type=std_logic lab=VDDCS}
C {devices/lab_pin.sym} -1510 20 2 1 {name=p8 sig_type=std_logic lab=VDDCS}
C {devices/lab_pin.sym} -230 180 2 1 {name=p16 sig_type=std_logic lab=VDDCS}
C {devices/lab_pin.sym} -140 560 2 1 {name=p28 sig_type=std_logic lab=VDDCS}
C {devices/lab_pin.sym} 20 830 2 1 {name=p35 sig_type=std_logic lab=VDDCS}
C {devices/lab_pin.sym} -110 930 2 1 {name=p9 sig_type=std_logic lab=HSS_STOP}
C {devices/lab_pin.sym} -1810 1650 2 1 {name=p11 sig_type=std_logic lab=VDDCS}
C {sky130_fd_pr/pfet_01v8_hvt.sym} -1430 660 0 1 {name=M40
W=0.42
L=1
nf=1
mult=1
ad="expr('int((@nf + 1)/2) * @W / @nf * 0.29')"
pd="expr('2*int((@nf + 1)/2) * (@W / @nf + 0.29)')"
as="expr('int((@nf + 2)/2) * @W / @nf * 0.29')"
ps="expr('2*int((@nf + 2)/2) * (@W / @nf + 0.29)')"
nrd="expr('0.29 / @W ')" nrs="expr('0.29 / @W ')"
sa=0 sb=0 sd=0
model=pfet_01v8_hvt
spiceprefix=X
}
C {sky130_fd_pr/pfet_01v8_hvt.sym} -1150 660 0 1 {name=M8
W=0.42
L=1
nf=1
mult=1
ad="expr('int((@nf + 1)/2) * @W / @nf * 0.29')"
pd="expr('2*int((@nf + 1)/2) * (@W / @nf + 0.29)')"
as="expr('int((@nf + 2)/2) * @W / @nf * 0.29')"
ps="expr('2*int((@nf + 2)/2) * (@W / @nf + 0.29)')"
nrd="expr('0.29 / @W ')" nrs="expr('0.29 / @W ')"
sa=0 sb=0 sd=0
model=pfet_01v8_hvt
spiceprefix=X
}
C {sky130_fd_pr/pfet_01v8_hvt.sym} -1150 760 0 1 {name=M26
W=0.42
L=1
nf=1
mult=1
ad="expr('int((@nf + 1)/2) * @W / @nf * 0.29')"
pd="expr('2*int((@nf + 1)/2) * (@W / @nf + 0.29)')"
as="expr('int((@nf + 2)/2) * @W / @nf * 0.29')"
ps="expr('2*int((@nf + 2)/2) * (@W / @nf + 0.29)')"
nrd="expr('0.29 / @W ')" nrs="expr('0.29 / @W ')"
sa=0 sb=0 sd=0
model=pfet_01v8_hvt
spiceprefix=X
}
C {sky130_fd_pr/pfet_01v8_hvt.sym} -1040 760 0 0 {name=M27
W=0.42
L=1
nf=1
mult=1
ad="expr('int((@nf + 1)/2) * @W / @nf * 0.29')"
pd="expr('2*int((@nf + 1)/2) * (@W / @nf + 0.29)')"
as="expr('int((@nf + 2)/2) * @W / @nf * 0.29')"
ps="expr('2*int((@nf + 2)/2) * (@W / @nf + 0.29)')"
nrd="expr('0.29 / @W ')" nrs="expr('0.29 / @W ')"
sa=0 sb=0 sd=0
model=pfet_01v8_hvt
spiceprefix=X
}
C {sky130_fd_pr/pfet_01v8_hvt.sym} -1040 660 0 0 {name=M36
W=0.42
L=1
nf=1
mult=1
ad="expr('int((@nf + 1)/2) * @W / @nf * 0.29')"
pd="expr('2*int((@nf + 1)/2) * (@W / @nf + 0.29)')"
as="expr('int((@nf + 2)/2) * @W / @nf * 0.29')"
ps="expr('2*int((@nf + 2)/2) * (@W / @nf + 0.29)')"
nrd="expr('0.29 / @W ')" nrs="expr('0.29 / @W ')"
sa=0 sb=0 sd=0
model=pfet_01v8_hvt
spiceprefix=X
}
C {sky130_fd_pr/pfet_01v8_hvt.sym} -1040 860 0 0 {name=M37
W=0.42
L=1
nf=1
mult=1
ad="expr('int((@nf + 1)/2) * @W / @nf * 0.29')"
pd="expr('2*int((@nf + 1)/2) * (@W / @nf + 0.29)')"
as="expr('int((@nf + 2)/2) * @W / @nf * 0.29')"
ps="expr('2*int((@nf + 2)/2) * (@W / @nf + 0.29)')"
nrd="expr('0.29 / @W ')" nrs="expr('0.29 / @W ')"
sa=0 sb=0 sd=0
model=pfet_01v8_hvt
spiceprefix=X
}
C {devices/capa.sym} 211 -220 0 0 {name=C2
m=1
value=10n
footprint=1206
device="ceramic capacitor"}
C {devices/lab_pin.sym} 211 -190 1 1 {name=p41 sig_type=std_logic lab=0
value=1n}
C {LELO_SVOD_SKY130A/LELO_COLD_START.sym} 31 -280 0 0 {name=x19}
C {devices/lab_pin.sym} -89 -250 1 1 {name=p43 sig_type=std_logic lab=0}
C {devices/lab_pin.sym} 260 -280 2 0 {name=p86 sig_type=std_logic lab=VDDCS}
C {sky130_fd_pr/nfet_03v3_nvt.sym} 310 1080 0 0 {name=M38
W=1
L=0.5
nf=1
mult=1
ad="expr('int((@nf + 1)/2) * @W / @nf * 0.29')"
pd="expr('2*int((@nf + 1)/2) * (@W / @nf + 0.29)')"
as="expr('int((@nf + 2)/2) * @W / @nf * 0.29')"
ps="expr('2*int((@nf + 2)/2) * (@W / @nf + 0.29)')"
nrd="expr('0.29 / @W ')" nrs="expr('0.29 / @W ')"
sa=0 sb=0 sd=0
model=nfet_03v3_nvt
spiceprefix=X
}
C {devices/lab_pin.sym} 330 1110 3 0 {name=p32 sig_type=std_logic lab=0}
C {devices/lab_pin.sym} 290 1080 3 0 {name=p49 sig_type=std_logic lab=0}
C {devices/lab_pin.sym} 940 40 2 0 {name=p60 sig_type=std_logic lab=VDDCS}
